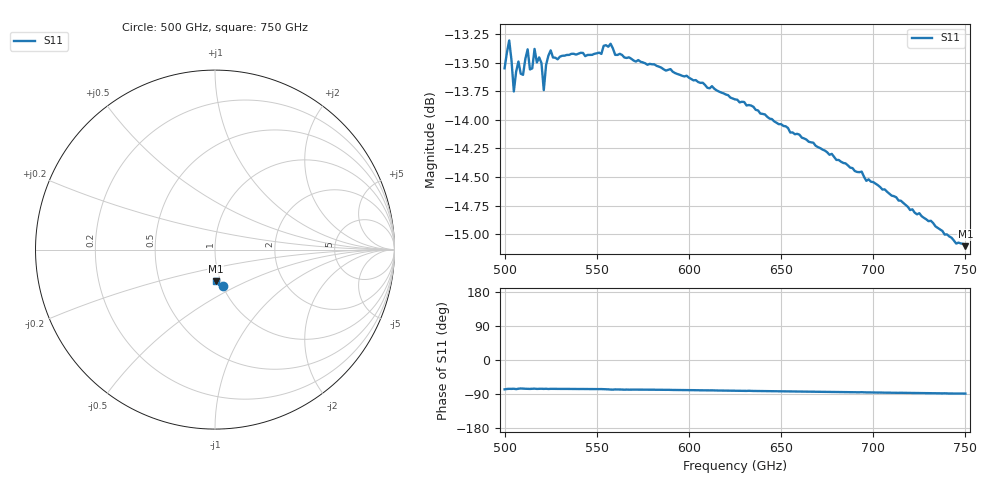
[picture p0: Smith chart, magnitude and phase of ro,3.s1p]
!Created with mwavepy.
! Created with skrf 2.0.1 (http://scikit-rf.org).
# GHz S RI R 50.0
!freq ReS11 ImS11
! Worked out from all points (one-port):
!   201 points, 500 GHz to 750 GHz, reference 50 ohm
!   lowest |S11| = -15.1 dB at 750 GHz (marker M1), VSWR 1.43, Z = 47.4 - j17.2 ohm
!   |S11| at or under -10 dB: start of sweep to end of sweep
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500  0.0455 -0.2051
502.5  0.0521 -0.2097
505  0.0505 -0.199
506.25  0.0474 -0.204
507.5  0.0518 -0.2051
510  0.0518 -0.2022
512.5  0.0519 -0.2078
513.75  0.0497 -0.2039
515  0.0514 -0.2037
516.25  0.0534 -0.2075
517.5  0.05 -0.2053
520  0.0517 -0.2048
521.25  0.0488 -0.1997
522.5  0.0515 -0.2044
525  0.0515 -0.2077
526.25  0.0507 -0.2063
531.25  0.0503 -0.2068
552.5  0.0489 -0.2075
553.75  0.0484 -0.2094
557.5  0.0447 -0.2107
560  0.0455 -0.2081
562.5  0.045 -0.2084
593.75  0.0391 -0.2052
625  0.0318 -0.2012
656.25  0.0246 -0.1955
687.5  0.0159 -0.1895
718.75  0.0101 -0.1825
750  0.00392 -0.1757
